#************************************************************************************
# Copyright        : (c) All Rights Reserved
# Company          : X-FAB Global Services GmbH
# Address          : Haarbergstr. 67,  D-99097 Erfurt, Germany
#
# File             : xh018_xx43_MET4_METMID_METTHK_D_CELLS_HD_mprobe.lef
# Description      : LEF file for Library D_CELLS_HD
#                  : XH018, Digital Standard Cell Logic Library, 
#                  : 1.8V, 1.2V Standard Speed & Low Power, High Density routing pitch
#
# Technology       : XH018 - 180 nm Modular Mixed Signal HV CMOS
# Lib_version      : 6.0.0, Jun 18, 2025
#
# #######################################################################
#
#  Copyright (c) X-FAB Global Services GmbH. All rights reserved.
#  This Design Kit data and the associated documentation are
#  confidential and proprietary to X-FAB Global Services GmbH.
#  
#  DISCLAIMER
#  The information furnished herein by X-FAB Global Services GmbH (X-FAB) 
#  is substantially correct and accurate. However, X-FAB shall not be 
#  liable to licensee or any third party for any damages, including but 
#  not limited to property damage, loss of profits, loss of use, 
#  interruption of business or indirect, special, incidental or 
#  consequential damages, of any kind, in connection with or arising out 
#  of the furnishing, performance or use of the technical data. 
#  No obligation or liability to licensee or any third party shall arise 
#  or flow out of X-FAB rendering technical or other services.
#  
#  X-FAB makes no warranty, express, implied, statutory, or descriptive 
#  of the information contained herein or of warranties of 
#  merchantability, fitness for a particular purpose, or non-infringement.
#  X-FAB reserves the right to change specifications and prices at any 
#  time and without notice. Therefore, prior to designing this product 
#  into a system, it is necessary to check with X-FAB for current 
#  information. The products listed herein are intended for use in 
#  standard commercial applications. Applications requiring extended 
#  temperature range, unusual environmental requirements, or high 
#  reliability applications, such as military, medical life-support 
#  or life-sustaining equipment are specifically not recommended without 
#  additional processing by X-FAB for each application.
#
#************************************************************************************

VERSION 5.7 ;
BUSBITCHARS "[]" ;
DIVIDERCHAR "/" ;

 MANUFACTURINGGRID    0.005000 ;
SITE core_hd
    SYMMETRY Y  ;
    CLASS CORE  ;
    SIZE 0.560 BY 4.480 ;
END core_hd

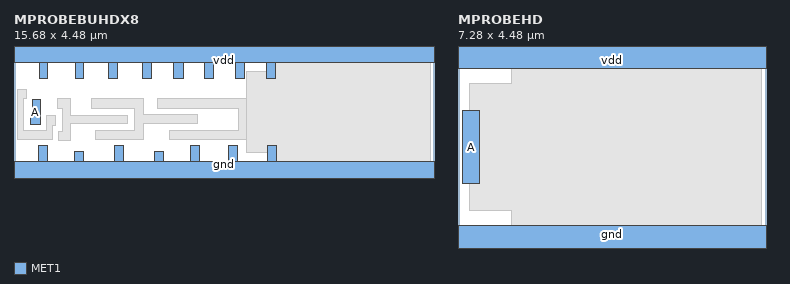
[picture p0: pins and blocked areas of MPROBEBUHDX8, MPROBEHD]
MACRO MPROBEBUHDX8
  CLASS CORE ;
  ORIGIN 0 0 ;
  FOREIGN MPROBEBUHDX8 0 0 ;
  SIZE 15.68 BY 4.48 ;
  SYMMETRY X Y ;
  SITE core_hd ;
  PIN A
    DIRECTION INPUT ;
    USE SIGNAL ;
    ANTENNAMODEL OXIDE1 ;
      ANTENNAGATEAREA 0.414 LAYER MET1 ;
    PORT
      LAYER MET1 ;
        POLYGON 0.98 2.69 0.7 2.69 0.7 2.16 0.6 2.16 0.6 1.79 0.98 1.79 ;
    END
  END A
  PIN vdd
    DIRECTION INOUT ;
    USE POWER ;
    SHAPE ABUTMENT ;
    NETEXPR "power_vdd vdd!" ;
    PORT
      LAYER MET1 ;
        RECT 9.42 3.49 9.76 4.08 ;
        RECT 8.27 3.49 8.61 4.08 ;
        RECT 7.12 3.49 7.46 4.08 ;
        RECT 5.97 3.49 6.31 4.08 ;
        RECT 4.78 3.49 5.12 4.08 ;
        RECT 3.51 3.49 3.85 4.08 ;
        RECT 2.31 3.5 2.59 4.08 ;
        RECT 0.97 3.5 1.25 4.08 ;
        RECT 0 4.08 15.68 4.88 ;
    END
  END vdd
  PIN gnd
    DIRECTION INOUT ;
    USE GROUND ;
    SHAPE ABUTMENT ;
    NETEXPR "ground_gnd gnd!" ;
    PORT
      LAYER MET1 ;
        RECT 9.46 0.4 9.8 0.99 ;
        RECT 8.02 0.4 8.36 0.99 ;
        RECT 6.58 0.4 6.92 0.99 ;
        RECT 5.24 0.4 5.58 0.77 ;
        RECT 3.76 0.4 4.1 0.99 ;
        RECT 2.24 0.4 2.58 0.77 ;
        RECT 0.9 0.4 1.24 0.99 ;
        RECT 0 -0.4 15.68 0.4 ;
    END
  END gnd
  OBS
    LAYER MET1 ;
      POLYGON 15.565 3.85 9.76 3.85 9.76 3.49 9.665 3.49 9.665 3.11 9.185 3.11 9.185 2.74 5.34 2.74 5.34 2.38 8.37 2.38 8.37 1.55 5.8 1.55 5.8 1.22 9.665 1.22 9.665 0.99 9.8 0.99 9.8 0.63 15.565 0.63 ;
      POLYGON 6.86 2.145 4.82 2.145 4.82 2.74 2.895 2.74 2.895 2.38 4.505 2.38 4.505 1.54 3.04 1.54 3.04 1.22 4.82 1.22 4.82 1.805 6.86 1.805 ;
      POLYGON 4.23 2.1 2.1 2.1 2.1 2.735 1.61 2.735 1.61 2.38 1.82 2.38 1.82 1.51 1.67 1.51 1.67 1.17 2.1 1.17 2.1 1.82 4.23 1.82 ;
      POLYGON 1.54 2.1 1.21 2.1 1.21 1.54 0.37 1.54 0.37 2.74 0.47 2.74 0.47 3.08 0.14 3.08 0.14 1.22 1.44 1.22 1.44 1.745 1.54 1.745 ;
    LAYER MET2 ;
      POLYGON 15.565 5.04 9.665 5.04 9.665 3.11 9.185 3.11 9.185 1.37 9.665 1.37 9.665 -0.56 15.565 -0.56 ;
    LAYER MET3 ;
      POLYGON 15.565 5.04 9.665 5.04 9.665 3.11 9.185 3.11 9.185 1.37 9.665 1.37 9.665 -0.56 15.565 -0.56 ;
    LAYER MET4 ;
      POLYGON 15.565 5.04 9.665 5.04 9.665 3.11 9.185 3.11 9.185 1.37 9.665 1.37 9.665 -0.56 15.565 -0.56 ;
    LAYER METTPL ;
      POLYGON 15.565 5.04 9.665 5.04 9.665 3.74 8.68 3.74 8.68 0.74 9.665 0.74 9.665 -0.56 15.565 -0.56 ;
    LAYER METTP ;
      POLYGON 15.565 5.04 9.665 5.04 9.665 3.74 8.68 3.74 8.68 0.74 9.665 0.74 9.665 -0.56 15.565 -0.56 ;
  END
END MPROBEBUHDX8

MACRO MPROBEHD
  CLASS CORE ;
  ORIGIN 0 0 ;
  FOREIGN MPROBEHD 0 0 ;
  SIZE 7.28 BY 4.48 ;
  SYMMETRY X Y ;
  SITE core_hd ;
  PIN A
    DIRECTION INPUT ;
    USE SIGNAL ;
    ANTENNAPARTIALMETALAREA 20.999 LAYER MET1 ;
    ANTENNAPARTIALMETALAREA 35.995 LAYER MET2 ;
    ANTENNAPARTIALMETALSIDEAREA 11.3997 LAYER MET1 ;
    ANTENNAPARTIALMETALSIDEAREA 13.85835 LAYER MET2 ;
    ANTENNAPARTIALCUTAREA 0.1352 LAYER VIA1 ;
    ANTENNAPARTIALCUTAREA 0.1352 LAYER VIA2 ;
    PORT
      LAYER MET1 ;
        RECT 0.115 1.37 0.505 3.11 ;
    END
  END A
  PIN vdd
    DIRECTION INOUT ;
    USE POWER ;
    SHAPE ABUTMENT ;
    NETEXPR "power_vdd vdd!" ;
    PORT
      LAYER MET1 ;
        RECT 0 4.08 7.28 4.88 ;
    END
  END vdd
  PIN gnd
    DIRECTION INOUT ;
    USE GROUND ;
    SHAPE ABUTMENT ;
    NETEXPR "ground_gnd gnd!" ;
    PORT
      LAYER MET1 ;
        RECT 0 -0.4 7.28 0.4 ;
    END
  END gnd
  OBS
    LAYER MET4 ;
      POLYGON 7.165 5.04 1.265 5.04 1.265 3.74 0.28 3.74 0.28 0.74 1.265 0.74 1.265 -0.56 7.165 -0.56 ;
    LAYER METTPL ;
      POLYGON 7.165 5.04 1.265 5.04 1.265 3.74 0.28 3.74 0.28 0.74 1.265 0.74 1.265 -0.56 7.165 -0.56 ;
    LAYER MET1 ;
      POLYGON 7.165 3.85 1.265 3.85 1.265 3.11 0.785 3.11 0.785 1.37 1.265 1.37 1.265 0.63 7.165 0.63 ;
    LAYER MET2 ;
      POLYGON 7.165 5.04 1.265 5.04 1.265 3.74 0.28 3.74 0.28 3.39 0.785 3.39 0.785 1.09 0.28 1.09 0.28 0.74 1.265 0.74 1.265 -0.56 7.165 -0.56 ;
    LAYER MET3 ;
      POLYGON 7.165 5.04 1.265 5.04 1.265 3.74 0.28 3.74 0.28 0.74 1.265 0.74 1.265 -0.56 7.165 -0.56 ;
    LAYER METTP ;
      POLYGON 7.165 5.04 1.265 5.04 1.265 3.74 0.28 3.74 0.28 0.74 1.265 0.74 1.265 -0.56 7.165 -0.56 ;
  END
END MPROBEHD

END LIBRARY
